VERSION 5.7 ;
  NOWIREEXTENSIONATPIN ON ;
  DIVIDERCHAR "/" ;
  BUSBITCHARS "[]" ;
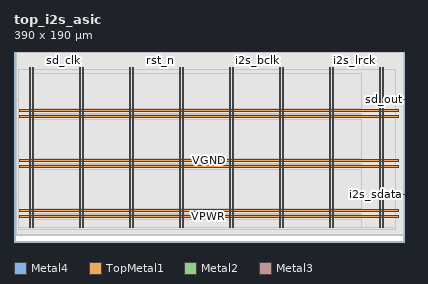
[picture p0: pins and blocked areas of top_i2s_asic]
MACRO top_i2s_asic
  CLASS BLOCK ;
  FOREIGN top_i2s_asic ;
  ORIGIN 0.000 0.000 ;
  SIZE 390.000 BY 190.000 ;
  PIN VGND
    DIRECTION INOUT ;
    USE GROUND ;
    PORT
      LAYER Metal4 ;
        RECT 18.260 14.900 19.260 174.100 ;
    END
    PORT
      LAYER Metal4 ;
        RECT 68.260 14.900 69.260 174.100 ;
    END
    PORT
      LAYER Metal4 ;
        RECT 118.260 14.900 119.260 174.100 ;
    END
    PORT
      LAYER Metal4 ;
        RECT 168.260 14.900 169.260 174.100 ;
    END
    PORT
      LAYER Metal4 ;
        RECT 218.260 14.900 219.260 174.100 ;
    END
    PORT
      LAYER Metal4 ;
        RECT 268.260 14.900 269.260 174.100 ;
    END
    PORT
      LAYER Metal4 ;
        RECT 318.260 14.900 319.260 174.100 ;
    END
    PORT
      LAYER Metal4 ;
        RECT 368.260 14.900 369.260 174.100 ;
    END
    PORT
      LAYER TopMetal1 ;
        RECT 5.760 30.120 384.000 32.120 ;
    END
    PORT
      LAYER TopMetal1 ;
        RECT 5.760 80.120 384.000 82.120 ;
    END
    PORT
      LAYER TopMetal1 ;
        RECT 5.760 130.120 384.000 132.120 ;
    END
  END VGND
  PIN VPWR
    DIRECTION INOUT ;
    USE POWER ;
    PORT
      LAYER Metal4 ;
        RECT 15.260 14.900 16.260 174.100 ;
    END
    PORT
      LAYER Metal4 ;
        RECT 65.260 14.900 66.260 174.100 ;
    END
    PORT
      LAYER Metal4 ;
        RECT 115.260 14.900 116.260 174.100 ;
    END
    PORT
      LAYER Metal4 ;
        RECT 165.260 14.900 166.260 174.100 ;
    END
    PORT
      LAYER Metal4 ;
        RECT 215.260 14.900 216.260 174.100 ;
    END
    PORT
      LAYER Metal4 ;
        RECT 265.260 14.900 266.260 174.100 ;
    END
    PORT
      LAYER Metal4 ;
        RECT 315.260 14.900 316.260 174.100 ;
    END
    PORT
      LAYER Metal4 ;
        RECT 365.260 14.900 366.260 174.100 ;
    END
    PORT
      LAYER TopMetal1 ;
        RECT 5.760 24.120 384.000 26.120 ;
    END
    PORT
      LAYER TopMetal1 ;
        RECT 5.760 74.120 384.000 76.120 ;
    END
    PORT
      LAYER TopMetal1 ;
        RECT 5.760 124.120 384.000 126.120 ;
    END
  END VPWR
  PIN i2s_bclk
    DIRECTION INPUT ;
    USE SIGNAL ;
    ANTENNAGATEAREA 0.180700 ;
    PORT
      LAYER Metal2 ;
        RECT 243.160 189.600 243.560 190.000 ;
    END
  END i2s_bclk
  PIN i2s_lrck
    DIRECTION INPUT ;
    USE SIGNAL ;
    ANTENNAGATEAREA 0.180700 ;
    PORT
      LAYER Metal2 ;
        RECT 340.120 189.600 340.520 190.000 ;
    END
  END i2s_lrck
  PIN i2s_sdata
    DIRECTION INPUT ;
    USE SIGNAL ;
    ANTENNAGATEAREA 0.180700 ;
    PORT
      LAYER Metal3 ;
        RECT 389.600 47.260 390.000 47.660 ;
    END
  END i2s_sdata
  PIN rst_n
    DIRECTION INPUT ;
    USE SIGNAL ;
    ANTENNAGATEAREA 0.180700 ;
    PORT
      LAYER Metal2 ;
        RECT 146.200 189.600 146.600 190.000 ;
    END
  END rst_n
  PIN sd_clk
    DIRECTION INPUT ;
    USE SIGNAL ;
    ANTENNAGATEAREA 0.725400 ;
    PORT
      LAYER Metal2 ;
        RECT 49.240 189.600 49.640 190.000 ;
    END
  END sd_clk
  PIN sd_out
    DIRECTION OUTPUT ;
    USE SIGNAL ;
    ANTENNADIFFAREA 0.708600 ;
    PORT
      LAYER Metal3 ;
        RECT 389.600 142.180 390.000 142.580 ;
    END
  END sd_out
  OBS
      LAYER GatPoly ;
        RECT 5.760 14.970 384.000 174.030 ;
      LAYER Metal1 ;
        RECT 5.760 14.900 384.000 174.100 ;
      LAYER Metal2 ;
        RECT 2.775 189.390 49.030 189.985 ;
        RECT 49.850 189.390 145.990 189.985 ;
        RECT 146.810 189.390 242.950 189.985 ;
        RECT 243.770 189.390 339.910 189.985 ;
        RECT 340.730 189.390 389.865 189.985 ;
        RECT 2.775 6.995 389.865 189.390 ;
      LAYER Metal3 ;
        RECT 2.735 142.790 389.905 189.940 ;
        RECT 2.735 141.970 389.390 142.790 ;
        RECT 2.735 47.870 389.905 141.970 ;
        RECT 2.735 47.050 389.390 47.870 ;
        RECT 2.735 7.040 389.905 47.050 ;
      LAYER Metal4 ;
        RECT 4.700 14.690 15.050 172.765 ;
        RECT 16.470 14.690 18.050 172.765 ;
        RECT 19.470 14.690 65.050 172.765 ;
        RECT 66.470 14.690 68.050 172.765 ;
        RECT 69.470 14.690 115.050 172.765 ;
        RECT 116.470 14.690 118.050 172.765 ;
        RECT 119.470 14.690 165.050 172.765 ;
        RECT 166.470 14.690 168.050 172.765 ;
        RECT 169.470 14.690 215.050 172.765 ;
        RECT 216.470 14.690 218.050 172.765 ;
        RECT 219.470 14.690 265.050 172.765 ;
        RECT 266.470 14.690 268.050 172.765 ;
        RECT 269.470 14.690 315.050 172.765 ;
        RECT 316.470 14.690 318.050 172.765 ;
        RECT 319.470 14.690 365.050 172.765 ;
        RECT 366.470 14.690 368.050 172.765 ;
        RECT 369.470 14.690 381.220 172.765 ;
        RECT 4.700 12.875 381.220 14.690 ;
      LAYER TopMetal1 ;
        RECT 15.980 133.760 347.860 168.900 ;
        RECT 15.980 127.760 347.860 128.480 ;
        RECT 15.980 83.760 347.860 122.480 ;
        RECT 15.980 77.760 347.860 78.480 ;
        RECT 15.980 33.760 347.860 72.480 ;
        RECT 15.980 27.760 347.860 28.480 ;
        RECT 15.980 14.500 347.860 22.480 ;
  END
END top_i2s_asic
END LIBRARY

